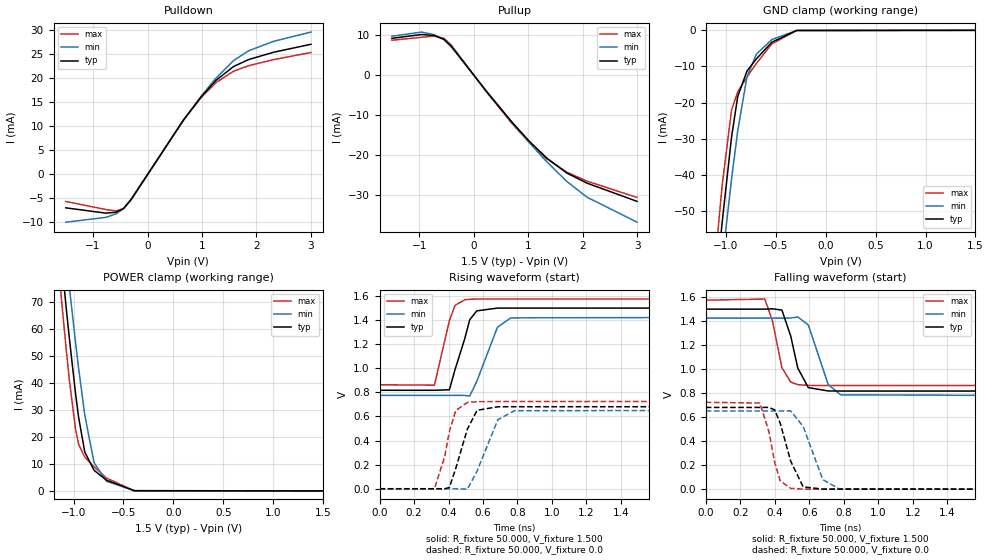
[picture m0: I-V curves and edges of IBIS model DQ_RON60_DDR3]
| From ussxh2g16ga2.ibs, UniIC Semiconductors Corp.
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|   Model DQ_RON60_DDR3
[Model] DQ_RON60_DDR3
Model_type I/O
Vinl =  0.615V
Vinh =  0.885V
Vmeas =  0.750V
Rref =  50.000
Vref =  0.750V
C_comp   0.966pF   0.965pF   0.967pF
[Model Spec]
Vinh   0.885V   0.847V   0.922V
Vinl   0.615V   0.577V   0.652V
Vmeas   0.750V   0.712V   0.787V
Vref   0.750V   0.712V   0.787V
Rref   50.000   NA   NA
[Temperature Range]   25.000   0.105k   -40.000
[Voltage Range]   1.500V   1.425V   1.575V
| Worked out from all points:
|   slope of the pulldown table from 0 to 0.225 V, typ, clamps not added: 56.5 ohm
|   slope of the pullup table from 0 to 0.225 V, typ, clamps not added: 57.4 ohm
|   GND clamp passes 1 mA (typ) near -0.43 V on its own axis
|   POWER clamp passes 1 mA (typ) near -0.52 V on its own axis
|   rising waveform, R_fixture 50.000, V_fixture 1.500: 20-80 % time 81.7ps typ, 104ps min, 66.8ps max; typ from 0.818 V to 1.5 V
|   rising waveform, R_fixture 50.000, V_fixture 0.0: 20-80 % time 84.4ps typ, 108ps min, 70.8ps max; typ from 0 V to 0.681 V
|   falling waveform, R_fixture 50.000, V_fixture 1.500: 20-80 % time 71.8ps typ, 88.2ps min, 63ps max; typ from 1.5 V to 0.818 V
|   falling waveform, R_fixture 50.000, V_fixture 0.0: 20-80 % time 76.4ps typ, 98.1ps min, 63.7ps max; typ from 0.681 V to 0 V
[Pulldown]
|Voltage   I(typ)   I(min)   I(max)
-1.5V     -7.077mA   -10.07mA   -5.748mA
-764mV    -8.187mA   -9.067mA   -7.434mA
-580mV    -7.998mA   -8.342mA   -7.72mA
-442mV    -7.252mA   -7.263mA   -7.217mA
-304mV    -5.41mA    -5.303mA   -5.451mA
662mV     11.26mA    11.19mA    11.24mA
984mV     16.05mA    16.16mA    15.87mA
1.26V     19.52mA    20mA       19.05mA
1.582V    22.39mA    23.63mA    21.41mA
1.858V    23.83mA    25.67mA    22.55mA
2.318V    25.36mA    27.63mA    23.82mA
3V        27.01mA    29.55mA    25.3mA
[Pullup]
|Voltage   I(typ)   I(min)   I(max)
-1.5V     9.205mA    9.732mA    8.722mA
-956mV    10.16mA    10.77mA    9.463mA
-726mV    9.917mA    10.15mA    9.772mA
-542mV    8.946mA    8.822mA    9.189mA
-404mV    7.122mA    6.977mA    7.402mA
240mV     -4.178mA   -4.138mA   -4.333mA
700mV     -11.77mA   -11.83mA   -12.12mA
1.022V    -16.63mA   -16.97mA   -16.98mA
1.344V    -20.88mA   -21.8mA    -21.06mA
1.712V    -24.62mA   -26.74mA   -24.4mA
2.08V     -27.14mA   -30.67mA   -26.64mA
3V        -31.73mA   -36.95mA   -30.74mA
[GND_clamp]
|Voltage   I(typ)   I(min)   I(max)
-1.5V     -194.2mA   -190.4mA   -200.2mA
-1.128V   -79.38mA   -87.94mA   -71.42mA
-1.097V   -70.36mA   -79.78mA   -61.46mA
-1.066V   -61.52mA   -71.73mA   -51.83mA
-1.035V   -52.91mA   -63.81mA   -42.69mA
-942mV    -29.54mA   -41.22mA   -22.03mA
-880mV    -18.29mA   -27.76mA   -17.02mA
-787mV    -11.24mA   -12.81mA   -12.91mA
-694mV    -7.909mA   -6.61mA    -9.178mA
-539mV    -3.3mA     -2.554mA   -3.76mA
-291mV    -42.28uA   -49.13uA   -38.22uA
1.5V      0A         0A         0A
[POWER_clamp]
|Voltage   I(typ)   I(min)   I(max)
-1.5V     238.9mA    246.7mA    236.4mA
-1.135V   91.01mA    108.5mA    76.96mA
-1.104V   79.29mA    97.43mA    64.51mA
-1.073V   67.84mA    86.49mA    52.53mA
-1.042V   56.75mA    75.77mA    41.28mA
-980mV    36.24mA    55.21mA    22.93mA
-949mV    27.34mA    45.53mA    17.31mA
-887mV    14.41mA    28.1mA     12.52mA
-794mV    7.645mA    10.44mA    8.93mA
-670mV    3.99mA     3.593mA    4.77mA
-391mV    72.25uA    122.5uA    45.94uA
1.5V      0A         0A         0A
[Ramp]
| variable   typ   min   max
dV/dt_r   0.409/84.474p   0.391/0.108n   0.434/70.864p
dV/dt_f   0.409/71.683p   0.390/87.910p   0.427/62.993p
R_load = 50.000
[Rising Waveform]
R_fixture= 50.000
V_fixture= 1.500
V_fixture_min= 1.425
V_fixture_max= 1.575
|time   V(typ)   V(min)   V(max)
0s        817.6mV    775.4mV    863.6mV
318ps     817.5mV    775.4mV    859.9mV
405ps     821.8mV    775.4mV    1.396V
438ps     990.5mV    775.4mV    1.523V
494ps     1.245V     775mV      1.569V
523ps     1.403V     769.9mV    1.573V
564ps     1.477V     891.3mV    1.575V
684ps     1.5V       1.341V     1.575V
762ps     1.5V       1.419V     1.575V
3ns       1.5V       1.425V     1.575V
[Rising Waveform]
R_fixture= 50.000
V_fixture= 0.0
V_fixture_min= 0.0
V_fixture_max= 0.0
|time   V(typ)   V(min)   V(max)
0s        223nV      2.174uV    104.7nV
318ps     -36.75uV   4.347uV    -722.7uV
378ps     -789.6uV   4.407uV    268.1mV
405ps     11.05mV    -8.692uV   476mV
442ps     168.5mV    770.5nV    649.6mV
509ps     494.3mV    -3.544mV   716.4mV
566ps     651.4mV    147.3mV    722.8mV
686ps     680.5mV    572.8mV    723.8mV
783ps     681mV      648.1mV    723.8mV
3ns       681.1mV    651.4mV    723.8mV
[Falling Waveform]
R_fixture= 50.000
V_fixture= 1.500
V_fixture_min= 1.425
V_fixture_max= 1.575
|time   V(typ)   V(min)   V(max)
0s        1.5V       1.425V     1.575V
342ps     1.5V       1.425V     1.584V
386ps     1.503V     1.425V     1.403V
441ps     1.492V     1.425V     1.013V
492ps     1.276V     1.426V     892.5mV
533ps     1.009V     1.435V     871mV
594ps     846.3mV    1.368V     864.6mV
709ps     818.3mV    872.4mV    863.6mV
781ps     817.6mV    786mV      863.6mV
3ns       817.6mV    775.4mV    863.6mV
[Falling Waveform]
R_fixture= 50.000
V_fixture= 0.0
V_fixture_min= 0.0
V_fixture_max= 0.0
|time   V(typ)   V(min)   V(max)
0s        681.1mV    651.4mV    723.8mV
313ps     681mV      651.4mV    717.6mV
366ps     681.5mV    651.4mV    479.3mV
399ps     660.4mV    651.4mV    223.9mV
431ps     550.8mV    651.3mV    69.25mV
492ps     232.8mV    652.2mV    6.928mV
564ps     19.6mV     522.7mV    460.1uV
678ps     316.2uV    79.14mV    5.411uV
771ps     10.14uV    3.522mV    366.2nV
3ns       258.2nV    2.202uV    185.5nV
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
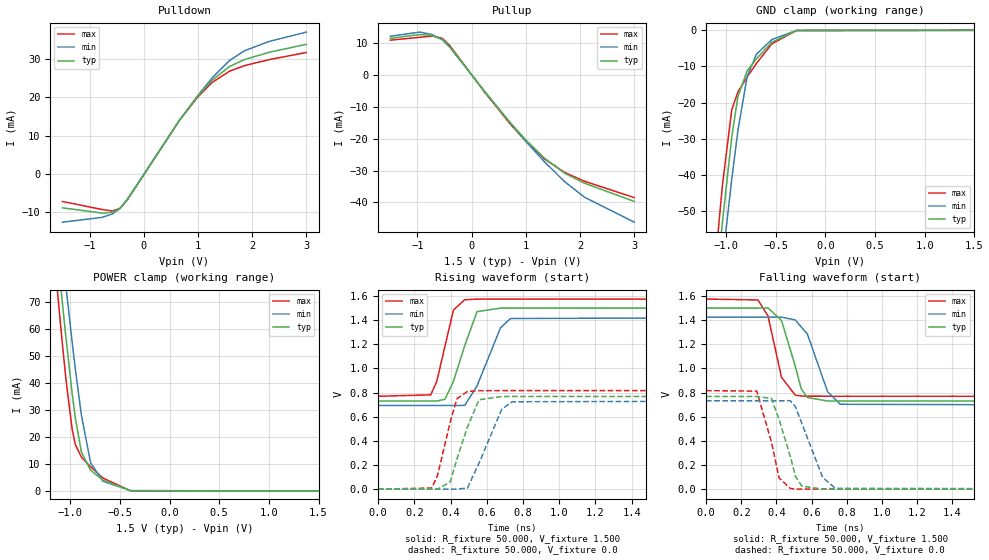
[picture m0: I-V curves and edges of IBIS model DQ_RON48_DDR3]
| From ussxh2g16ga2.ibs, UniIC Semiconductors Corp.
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|   Model DQ_RON48_DDR3
[Model] DQ_RON48_DDR3
Model_type I/O
Vinl =  0.615V
Vinh =  0.885V
Vmeas =  0.750V
Rref =  50.000
Vref =  0.750V
C_comp   0.966pF   0.965pF   0.967pF
[Model Spec]
Vinh   0.885V   0.847V   0.922V
Vinl   0.615V   0.577V   0.652V
Vmeas   0.750V   0.712V   0.787V
Vref   0.750V   0.712V   0.787V
Rref   50.000   NA   NA
[Temperature Range]   25.000   0.105k   -40.000
[Voltage Range]   1.500V   1.425V   1.575V
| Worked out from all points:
|   slope of the pulldown table from 0 to 0.225 V, typ, clamps not added: 45.2 ohm
|   slope of the pullup table from 0 to 0.225 V, typ, clamps not added: 45.9 ohm
|   GND clamp passes 1 mA (typ) near -0.43 V on its own axis
|   POWER clamp passes 1 mA (typ) near -0.52 V on its own axis
|   rising waveform, R_fixture 50.000, V_fixture 1.500: 20-80 % time 90.1ps typ, 119ps min, 72.2ps max; typ from 0.73 V to 1.5 V
|   rising waveform, R_fixture 50.000, V_fixture 0.0: 20-80 % time 91.2ps typ, 117ps min, 75.6ps max; typ from 0 V to 0.768 V
|   falling waveform, R_fixture 50.000, V_fixture 1.500: 20-80 % time 84.2ps typ, 105ps min, 72.3ps max; typ from 1.5 V to 0.73 V
|   falling waveform, R_fixture 50.000, V_fixture 0.0: 20-80 % time 90.2ps typ, 116ps min, 74.6ps max; typ from 0.768 V to 0 V
[Pulldown]
|Voltage   I(typ)   I(min)   I(max)
-1.5V     -8.855mA   -12.6mA    -7.198mA
-764mV    -10.24mA   -11.34mA   -9.305mA
-580mV    -10mA      -10.43mA   -9.66mA
-442mV    -9.069mA   -9.082mA   -9.029mA
-304mV    -6.766mA   -6.631mA   -6.819mA
662mV     14.08mA    14mA       14.06mA
984mV     20.07mA    20.21mA    19.85mA
1.26V     24.41mA    25.01mA    23.83mA
1.582V    28.01mA    29.57mA    26.79mA
1.858V    29.82mA    32.11mA    28.23mA
2.318V    31.73mA    34.58mA    29.82mA
3V        33.8mA     36.99mA    31.67mA
[Pullup]
|Voltage   I(typ)   I(min)   I(max)
-1.5V     11.52mA    12.17mA    10.93mA
-956mV    12.71mA    13.47mA    11.85mA
-726mV    12.41mA    12.69mA    12.23mA
-542mV    11.19mA    11.03mA    11.5mA
-404mV    8.909mA    8.725mA    9.263mA
240mV     -5.227mA   -5.175mA   -5.422mA
700mV     -14.73mA   -14.8mA    -15.17mA
1.022V    -20.8mA    -21.22mA   -21.25mA
1.344V    -26.12mA   -27.26mA   -26.36mA
1.712V    -30.8mA    -33.44mA   -30.54mA
2.08V     -33.96mA   -38.35mA   -33.35mA
3V        -39.7mA    -46.21mA   -38.49mA
[GND_clamp]
|Voltage   I(typ)   I(min)   I(max)
-1.5V     -194.2mA   -190.4mA   -200.2mA
-1.128V   -79.38mA   -87.94mA   -71.42mA
-1.097V   -70.36mA   -79.78mA   -61.46mA
-1.066V   -61.52mA   -71.73mA   -51.83mA
-1.035V   -52.91mA   -63.81mA   -42.69mA
-942mV    -29.54mA   -41.22mA   -22.03mA
-880mV    -18.29mA   -27.76mA   -17.02mA
-787mV    -11.24mA   -12.81mA   -12.91mA
-694mV    -7.909mA   -6.61mA    -9.178mA
-539mV    -3.3mA     -2.554mA   -3.76mA
-291mV    -42.28uA   -49.13uA   -38.22uA
1.5V      0A         0A         0A
[POWER_clamp]
|Voltage   I(typ)   I(min)   I(max)
-1.5V     238.9mA    246.7mA    236.4mA
-1.135V   91.01mA    108.5mA    76.96mA
-1.104V   79.29mA    97.43mA    64.51mA
-1.073V   67.84mA    86.49mA    52.53mA
-1.042V   56.75mA    75.77mA    41.28mA
-980mV    36.24mA    55.21mA    22.93mA
-949mV    27.34mA    45.53mA    17.31mA
-887mV    14.41mA    28.1mA     12.52mA
-794mV    7.645mA    10.44mA    8.93mA
-670mV    3.99mA     3.593mA    4.77mA
-391mV    72.25uA    122.5uA    45.94uA
1.5V      0A         0A         0A
[Ramp]
| variable   typ   min   max
dV/dt_r   0.461/90.981p   0.439/0.117n   0.490/75.637p
dV/dt_f   0.462/83.868p   0.439/0.105n   0.483/72.416p
R_load = 50.000
[Rising Waveform]
R_fixture= 50.000
V_fixture= 1.500
V_fixture_min= 1.425
V_fixture_max= 1.575
|time   V(typ)   V(min)   V(max)
0s        729.8mV    693.5mV    769.8mV
290ps     729.8mV    693.5mV    781.2mV
324ps     729.8mV    693.5mV    894.4mV
369ps     745.1mV    693.5mV    1.186V
416ps     894.5mV    693.6mV    1.485V
478ps     1.189V     694mV      1.569V
546ps     1.471V     855.1mV    1.575V
676ps     1.5V       1.338V     1.575V
731ps     1.5V       1.414V     1.575V
3ns       1.5V       1.425V     1.575V
[Rising Waveform]
R_fixture= 50.000
V_fixture= 0.0
V_fixture_min= 0.0
V_fixture_max= 0.0
|time   V(typ)   V(min)   V(max)
0s        208.5nV    1.952uV    107.7nV
296ps     -18.19uV   4.75uV     9.245mV
328ps     122.6uV    6.61uV     115.8mV
398ps     60.93mV    4.586uV    556.4mV
435ps     249.9mV    197.2uV    749.6mV
493ps     515.5mV    9.333mV    809.4mV
557ps     740.9mV    215.5mV    815.9mV
683ps     767.7mV    664.1mV    816.5mV
741ps     767.9mV    724.1mV    816.5mV
3ns       767.9mV    732.3mV    816.5mV
[Falling Waveform]
R_fixture= 50.000
V_fixture= 1.500
V_fixture_min= 1.425
V_fixture_max= 1.575
|time   V(typ)   V(min)   V(max)
0s        1.5V       1.425V     1.575V
295ps     1.5V       1.425V     1.568V
352ps     1.502V     1.425V     1.435V
429ps     1.397V     1.425V     926.7mV
507ps     1.02V      1.402V     778.6mV
541ps     831.9mV    1.344V     772.3mV
576ps     759.5mV    1.286V     770.4mV
691ps     730.3mV    807.4mV    769.8mV
763ps     729.9mV    703.4mV    769.8mV
3ns       729.8mV    693.5mV    769.8mV
[Falling Waveform]
R_fixture= 50.000
V_fixture= 0.0
V_fixture_min= 0.0
V_fixture_max= 0.0
|time   V(typ)   V(min)   V(max)
0s        767.9mV    732.3mV    816.5mV
288ps     767.9mV    732.3mV    812.1mV
372ps     751.8mV    732.3mV    388.2mV
415ps     577.3mV    732.2mV    93.48mV
479ps     271.5mV    732.9mV    6.137mV
508ps     106.7mV    683.2mV    1.781mV
545ps     24.69mV    542.6mV    357.2uV
663ps     202.6uV    97.43mV    2.2uV
735ps     10.31uV    6.917mV    389.8nV
3ns       217.6nV    1.935uV    247.7nV
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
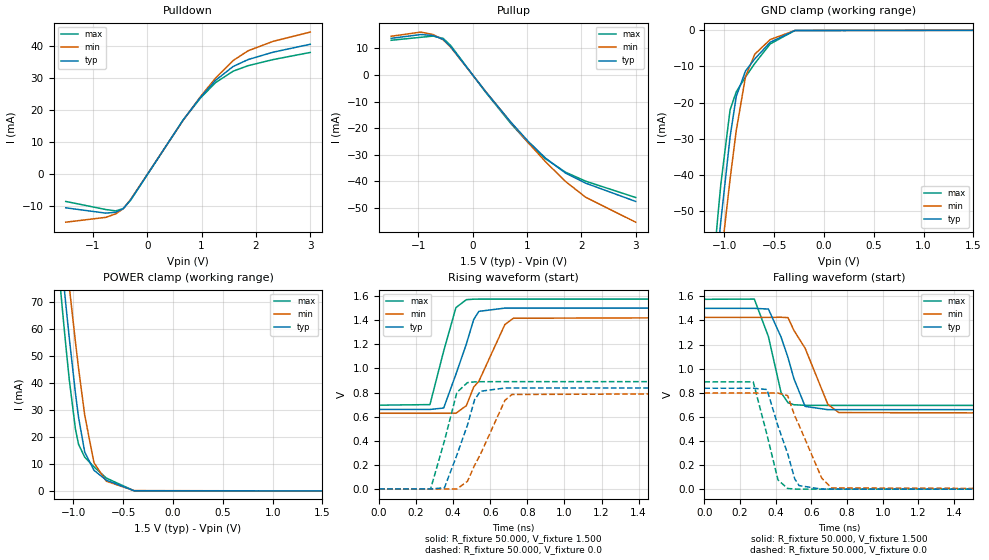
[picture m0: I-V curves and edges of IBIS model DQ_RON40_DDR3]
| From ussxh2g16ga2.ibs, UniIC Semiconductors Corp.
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|   Model DQ_RON40_DDR3
[Model] DQ_RON40_DDR3
Model_type I/O
Vinl =  0.615V
Vinh =  0.885V
Vmeas =  0.750V
Rref =  50.000
Vref =  0.750V
C_comp   0.966pF   0.965pF   0.967pF
[Model Spec]
Vinh   0.885V   0.847V   0.922V
Vinl   0.615V   0.577V   0.652V
Vmeas   0.750V   0.712V   0.787V
Vref   0.750V   0.712V   0.787V
Rref   50.000   NA   NA
[Temperature Range]   25.000   0.105k   -40.000
[Voltage Range]   1.500V   1.425V   1.575V
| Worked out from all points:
|   slope of the pulldown table from 0 to 0.225 V, typ, clamps not added: 37.7 ohm
|   slope of the pullup table from 0 to 0.225 V, typ, clamps not added: 38.3 ohm
|   GND clamp passes 1 mA (typ) near -0.43 V on its own axis
|   POWER clamp passes 1 mA (typ) near -0.52 V on its own axis
|   rising waveform, R_fixture 50.000, V_fixture 1.500: 20-80 % time 119ps typ, 164ps min, 91.2ps max; typ from 0.659 V to 1.5 V
|   rising waveform, R_fixture 50.000, V_fixture 0.0: 20-80 % time 108ps typ, 151ps min, 83.3ps max; typ from 0 V to 0.837 V
|   falling waveform, R_fixture 50.000, V_fixture 1.500: 20-80 % time 112ps typ, 153ps min, 86.8ps max; typ from 1.5 V to 0.659 V
|   falling waveform, R_fixture 50.000, V_fixture 0.0: 20-80 % time 107ps typ, 143ps min, 85.9ps max; typ from 0.837 V to 0 V
[Pulldown]
|Voltage   I(typ)   I(min)   I(max)
-1.5V     -10.61mA   -15.1mA    -8.617mA
-764mV    -12.27mA   -13.59mA   -11.14mA
-580mV    -11.99mA   -12.5mA    -11.57mA
-442mV    -10.87mA   -10.89mA   -10.82mA
-304mV    -8.107mA   -7.946mA   -8.167mA
662mV     16.87mA    16.77mA    16.84mA
984mV     24.04mA    24.22mA    23.77mA
1.26V     29.25mA    29.97mA    28.54mA
1.582V    33.55mA    35.41mA    32.08mA
1.858V    35.71mA    38.46mA    33.8mA
2.318V    38.01mA    41.4mA     35.7mA
3V        40.48mA    44.28mA    37.92mA
[Pullup]
|Voltage   I(typ)   I(min)   I(max)
-1.5V     13.8mA     14.58mA    13.07mA
-956mV    15.23mA    16.15mA    14.19mA
-726mV    14.86mA    15.21mA    14.65mA
-542mV    13.41mA    13.22mA    13.77mA
-404mV    10.67mA    10.45mA    11.09mA
240mV     -6.259mA   -6.199mA   -6.49mA
700mV     -17.64mA   -17.73mA   -18.15mA
1.022V    -24.91mA   -25.42mA   -25.43mA
1.344V    -31.28mA   -32.66mA   -31.54mA
1.712V    -36.88mA   -40.06mA   -36.54mA
2.08V     -40.64mA   -45.93mA   -39.9mA
3V        -47.51mA   -55.31mA   -46.03mA
[GND_clamp]
|Voltage   I(typ)   I(min)   I(max)
-1.5V     -194.2mA   -190.4mA   -200.2mA
-1.128V   -79.38mA   -87.94mA   -71.42mA
-1.097V   -70.36mA   -79.78mA   -61.46mA
-1.066V   -61.52mA   -71.73mA   -51.83mA
-1.035V   -52.91mA   -63.81mA   -42.69mA
-942mV    -29.54mA   -41.22mA   -22.03mA
-880mV    -18.29mA   -27.76mA   -17.02mA
-787mV    -11.24mA   -12.81mA   -12.91mA
-694mV    -7.909mA   -6.61mA    -9.178mA
-539mV    -3.3mA     -2.554mA   -3.76mA
-291mV    -42.28uA   -49.13uA   -38.22uA
1.5V      0A         0A         0A
[POWER_clamp]
|Voltage   I(typ)   I(min)   I(max)
-1.5V     238.9mA    246.7mA    236.4mA
-1.135V   91.01mA    108.5mA    76.96mA
-1.104V   79.29mA    97.43mA    64.51mA
-1.073V   67.84mA    86.49mA    52.53mA
-1.042V   56.75mA    75.77mA    41.28mA
-980mV    36.24mA    55.21mA    22.93mA
-949mV    27.34mA    45.53mA    17.31mA
-887mV    14.41mA    28.1mA     12.52mA
-794mV    7.645mA    10.44mA    8.93mA
-670mV    3.99mA     3.593mA    4.77mA
-391mV    72.25uA    122.5uA    45.94uA
1.5V      0A         0A         0A
[Ramp]
| variable   typ   min   max
dV/dt_r   0.502/0.108n   0.478/0.151n   0.534/83.194p
dV/dt_f   0.504/0.112n   0.478/0.153n   0.528/86.940p
R_load = 50.000
[Rising Waveform]
R_fixture= 50.000
V_fixture= 1.500
V_fixture_min= 1.425
V_fixture_max= 1.575
|time   V(typ)   V(min)   V(max)
0s        659.5mV    627.7mV    694.9mV
275ps     659.4mV    627.7mV    699.6mV
349ps     671.3mV    627.7mV    1.144V
415ps     951.4mV    627.8mV    1.504V
471ps     1.201V     690.6mV    1.57V
511ps     1.406V     845.4mV    1.574V
539ps     1.473V     894.2mV    1.575V
679ps     1.5V       1.364V     1.575V
725ps     1.5V       1.416V     1.575V
3ns       1.5V       1.425V     1.575V
[Rising Waveform]
R_fixture= 50.000
V_fixture= 0.0
V_fixture_min= 0.0
V_fixture_max= 0.0
|time   V(typ)   V(min)   V(max)
0s        197.4nV    1.776uV    110.9nV
278ps     -66.61uV   4.027uV    -1.742mV
353ps     9.699mV    -42.77uV   398.3mV
420ps     280.4mV    -46.21uV   800.1mV
477ps     529.5mV    63.01mV    882mV
516ps     741.7mV    197.1mV    888.3mV
547ps     810.2mV    287.2mV    889.5mV
679ps     837.3mV    734.5mV    889.9mV
717ps     837.4mV    783.5mV    889.9mV
3ns       837.4mV    797.4mV    889.9mV
[Falling Waveform]
R_fixture= 50.000
V_fixture= 1.500
V_fixture_min= 1.425
V_fixture_max= 1.575
|time   V(typ)   V(min)   V(max)
0s        1.5V       1.425V     1.575V
280ps     1.5V       1.425V     1.577V
359ps     1.494V     1.425V     1.266V
430ps     1.262V     1.426V     801.3mV
469ps     1.091V     1.423V     717mV
502ps     916.9mV    1.317V     700.5mV
565ps     686.6mV    1.169V     695.4mV
692ps     659.6mV    704.7mV    694.9mV
754ps     659.5mV    635.3mV    694.9mV
3ns       659.5mV    627.7mV    694.9mV
[Falling Waveform]
R_fixture= 50.000
V_fixture= 0.0
V_fixture_min= 0.0
V_fixture_max= 0.0
|time   V(typ)   V(min)   V(max)
0s        837.4mV    797.4mV    889.9mV
274ps     837.4mV    797.4mV    890mV
351ps     826.5mV    797.4mV    451.5mV
413ps     523.3mV    797.2mV    75.97mV
467ps     295mV      775.8mV    5.888mV
507ps     84.19mV    606.7mV    862.8uV
531ps     29.82mV    530.4mV    295.8uV
658ps     103.2uV    91.18mV    882.3nV
713ps     9.042uV    10.18mV    290.8nV
3ns       226.3nV    1.742uV    156.2nV
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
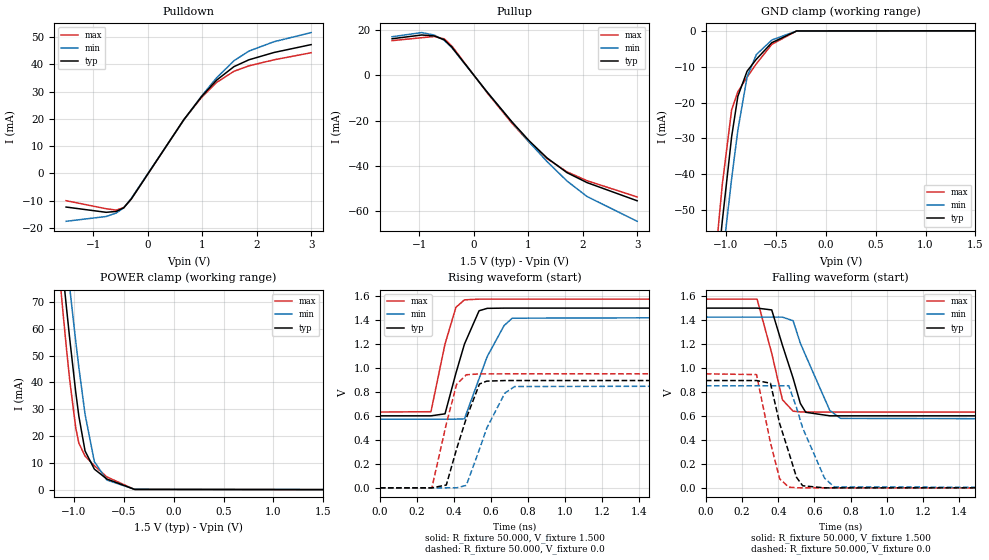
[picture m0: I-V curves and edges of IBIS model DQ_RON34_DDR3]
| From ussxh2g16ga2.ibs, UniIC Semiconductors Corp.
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|   Model DQ_RON34_DDR3
[Model] DQ_RON34_DDR3
Model_type I/O
Vinl =  0.615V
Vinh =  0.885V
Vmeas =  0.750V
Rref =  50.000
Vref =  0.750V
C_comp   0.966pF   0.965pF   0.967pF
[Model Spec]
Vinh   0.885V   0.847V   0.922V
Vinl   0.615V   0.577V   0.652V
Vmeas   0.750V   0.712V   0.787V
Vref   0.750V   0.712V   0.787V
Rref   50.000   NA   NA
[Temperature Range]   25.000   0.105k   -40.000
[Voltage Range]   1.500V   1.425V   1.575V
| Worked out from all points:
|   slope of the pulldown table from 0 to 0.225 V, typ, clamps not added: 32.3 ohm
|   slope of the pullup table from 0 to 0.225 V, typ, clamps not added: 32.8 ohm
|   GND clamp passes 1 mA (typ) near -0.43 V on its own axis
|   POWER clamp passes 1 mA (typ) near -0.52 V on its own axis
|   rising waveform, R_fixture 50.000, V_fixture 1.500: 20-80 % time 114ps typ, 154ps min, 89.1ps max; typ from 0.601 V to 1.5 V
|   rising waveform, R_fixture 50.000, V_fixture 0.0: 20-80 % time 108ps typ, 144ps min, 85.2ps max; typ from 0 V to 0.896 V
|   falling waveform, R_fixture 50.000, V_fixture 1.500: 20-80 % time 111ps typ, 147ps min, 90.2ps max; typ from 1.5 V to 0.601 V
|   falling waveform, R_fixture 50.000, V_fixture 0.0: 20-80 % time 102ps typ, 135ps min, 83.7ps max; typ from 0.896 V to 0 V
[Pulldown]
|Voltage   I(typ)   I(min)   I(max)
-1.5V     -12.39mA   -17.62mA   -10.06mA
-764mV    -14.32mA   -15.86mA   -13.01mA
-580mV    -13.99mA   -14.59mA   -13.51mA
-442mV    -12.68mA   -12.69mA   -12.62mA
-304mV    -9.452mA   -9.265mA   -9.524mA
662mV     19.67mA    19.56mA    19.64mA
984mV     28.04mA    28.24mA    27.73mA
1.26V     34.11mA    34.94mA    33.29mA
1.582V    39.13mA    41.29mA    37.42mA
1.858V    41.65mA    44.85mA    39.43mA
2.318V    44.33mA    48.28mA    41.64mA
3V        47.22mA    51.64mA    44.24mA
[Pullup]
|Voltage   I(typ)   I(min)   I(max)
-1.5V     16.11mA    17mA       15.27mA
-956mV    17.77mA    18.84mA    16.57mA
-726mV    17.35mA    17.74mA    17.1mA
-542mV    15.64mA    15.42mA    16.07mA
-404mV    12.45mA    12.19mA    12.94mA
240mV     -7.301mA   -7.23mA    -7.573mA
700mV     -20.57mA   -20.67mA   -21.19mA
1.022V    -29.06mA   -29.64mA   -29.68mA
1.344V    -36.49mA   -38.08mA   -36.81mA
1.712V    -43.02mA   -46.71mA   -42.65mA
2.08V     -47.41mA   -53.55mA   -46.57mA
3V        -55.43mA   -64.49mA   -53.74mA
[GND_clamp]
|Voltage   I(typ)   I(min)   I(max)
-1.5V     -194.2mA   -190.4mA   -200.2mA
-1.128V   -79.38mA   -87.94mA   -71.42mA
-1.097V   -70.36mA   -79.78mA   -61.46mA
-1.066V   -61.52mA   -71.73mA   -51.83mA
-1.035V   -52.91mA   -63.81mA   -42.69mA
-942mV    -29.54mA   -41.22mA   -22.03mA
-880mV    -18.29mA   -27.76mA   -17.02mA
-787mV    -11.24mA   -12.81mA   -12.91mA
-694mV    -7.909mA   -6.61mA    -9.178mA
-539mV    -3.3mA     -2.554mA   -3.76mA
-291mV    -42.28uA   -49.13uA   -38.22uA
1.5V      0A         0A         0A
[POWER_clamp]
|Voltage   I(typ)   I(min)   I(max)
-1.5V     238.9mA    246.7mA    236.4mA
-1.135V   91.01mA    108.5mA    76.96mA
-1.104V   79.29mA    97.43mA    64.51mA
-1.073V   67.84mA    86.49mA    52.53mA
-1.042V   56.75mA    75.77mA    41.28mA
-980mV    36.24mA    55.21mA    22.93mA
-949mV    27.34mA    45.53mA    17.31mA
-887mV    14.41mA    28.1mA     12.52mA
-794mV    7.645mA    10.44mA    8.93mA
-670mV    3.99mA     3.593mA    4.77mA
-391mV    72.25uA    122.5uA    45.94uA
1.5V      0A         0A         0A
[Ramp]
| variable   typ   min   max
dV/dt_r   0.537/0.108n   0.511/0.144n   0.571/85.190p
dV/dt_f   0.539/0.111n   0.511/0.148n   0.565/90.271p
R_load = 50.000
[Rising Waveform]
R_fixture= 50.000
V_fixture= 1.500
V_fixture_min= 1.425
V_fixture_max= 1.575
|time   V(typ)   V(min)   V(max)
0s        601.1mV    573mV      632.7mV
276ps     601mV      573mV      635.5mV
352ps     617.7mV    573mV      1.201V
411ps     957.8mV    573.4mV    1.507V
457ps     1.2V       575.7mV    1.569V
536ps     1.478V     911.3mV    1.575V
580ps     1.498V     1.096V     1.575V
671ps     1.5V       1.354V     1.575V
715ps     1.5V       1.416V     1.575V
3ns       1.5V       1.425V     1.575V
[Rising Waveform]
R_fixture= 50.000
V_fixture= 0.0
V_fixture_min= 0.0
V_fixture_max= 0.0
|time   V(typ)   V(min)   V(max)
0s        187.9nV    1.628uV    113.1nV
281ps     -80.66uV   4.392uV    278uV
359ps     23.7mV     -61.9uV    534.3mV
415ps     326.8mV    506.5uV    864.9mV
467ps     581.1mV    20.58mV    943.8mV
538ps     866.5mV    321.3mV    951.1mV
577ps     890.5mV    497.2mV    951.3mV
675ps     895.5mV    790.3mV    951.4mV
728ps     895.6mV    845.7mV    951.4mV
3ns       895.6mV    851.7mV    951.4mV
[Falling Waveform]
R_fixture= 50.000
V_fixture= 1.500
V_fixture_min= 1.425
V_fixture_max= 1.575
|time   V(typ)   V(min)   V(max)
0s        1.5V       1.425V     1.575V
283ps     1.5V       1.425V     1.575V
364ps     1.485V     1.425V     1.123V
423ps     1.191V     1.425V     735.6mV
482ps     916.2mV    1.395V     639.9mV
522ps     704.9mV    1.208V     633.9mV
552ps     630.6mV    1.103V     633mV
685ps     601.2mV    645.9mV    632.7mV
745ps     601.1mV    579.6mV    632.7mV
3ns       601.1mV    573mV      632.7mV
[Falling Waveform]
R_fixture= 50.000
V_fixture= 0.0
V_fixture_min= 0.0
V_fixture_max= 0.0
|time   V(typ)   V(min)   V(max)
0s        895.6mV    851.7mV    951.4mV
280ps     895.5mV    851.7mV    945.4mV
357ps     873.1mV    851.7mV    375.7mV
408ps     535.8mV    851.3mV    75.5mV
458ps     298.1mV    852.5mV    5.725mV
501ps     87.93mV    669.7mV    607.7uV
535ps     17.57mV    499.2mV    103uV
656ps     52.39uV    80.98mV    506.7nV
709ps     4.46uV     8.242mV    247.8nV
3ns       165.2nV    1.573uV    89.97nV
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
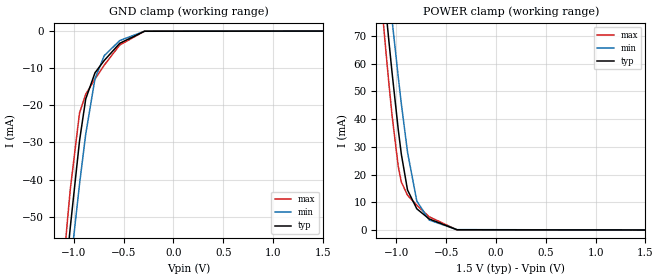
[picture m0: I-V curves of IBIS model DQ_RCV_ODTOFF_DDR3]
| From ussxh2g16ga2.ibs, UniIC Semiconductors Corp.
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|   Model DQ_RCV_ODTOFF_DDR3
[Model] DQ_RCV_ODTOFF_DDR3
Model_type Input
Vinl =  0.615V
Vinh =  0.885V
C_comp   0.966pF   0.965pF   0.967pF
[Model Spec]
Vinh   0.885V   0.847V   0.922V
Vinl   0.615V   0.577V   0.652V
[Temperature Range]   25.000   0.105k   -40.000
[Voltage Range]   1.500V   1.425V   1.575V
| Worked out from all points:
|   GND clamp passes 1 mA (typ) near -0.43 V on its own axis
|   POWER clamp passes 1 mA (typ) near -0.52 V on its own axis
[GND_clamp]
|Voltage   I(typ)   I(min)   I(max)
-1.5V     -194.2mA   -190.4mA   -200.2mA
-1.128V   -79.38mA   -87.94mA   -71.42mA
-1.097V   -70.36mA   -79.78mA   -61.46mA
-1.066V   -61.52mA   -71.73mA   -51.83mA
-1.035V   -52.91mA   -63.81mA   -42.69mA
-942mV    -29.54mA   -41.22mA   -22.03mA
-880mV    -18.29mA   -27.76mA   -17.02mA
-787mV    -11.24mA   -12.81mA   -12.91mA
-694mV    -7.909mA   -6.61mA    -9.178mA
-539mV    -3.3mA     -2.554mA   -3.76mA
-291mV    -42.28uA   -49.13uA   -38.22uA
1.5V      0A         0A         0A
[POWER_clamp]
|Voltage   I(typ)   I(min)   I(max)
-1.5V     238.9mA    246.7mA    236.4mA
-1.135V   91.01mA    108.5mA    76.96mA
-1.104V   79.29mA    97.43mA    64.51mA
-1.073V   67.84mA    86.49mA    52.53mA
-1.042V   56.75mA    75.77mA    41.28mA
-980mV    36.24mA    55.21mA    22.93mA
-949mV    27.34mA    45.53mA    17.31mA
-887mV    14.41mA    28.1mA     12.52mA
-794mV    7.645mA    10.44mA    8.93mA
-670mV    3.99mA     3.593mA    4.77mA
-391mV    72.25uA    122.5uA    45.94uA
1.5V      0A         0A         0A
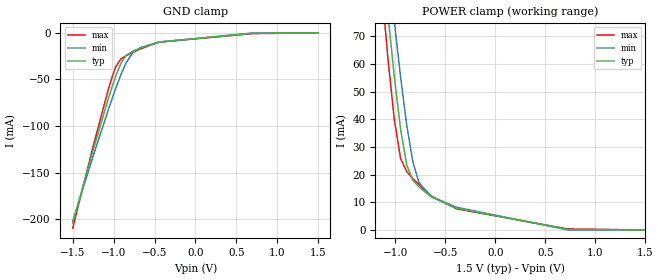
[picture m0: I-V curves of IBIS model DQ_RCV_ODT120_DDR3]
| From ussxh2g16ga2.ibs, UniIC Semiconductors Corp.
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|   Model DQ_RCV_ODT120_DDR3
[Model] DQ_RCV_ODT120_DDR3
Model_type Input
Vinl =  0.615V
Vinh =  0.885V
C_comp   0.966pF   0.965pF   0.967pF
[Model Spec]
Vinh   0.885V   0.847V   0.922V
Vinl   0.615V   0.577V   0.652V
[Temperature Range]   25.000   0.105k   -40.000
[Voltage Range]   1.500V   1.425V   1.575V
[GND_clamp]
|Voltage   I(typ)   I(min)   I(max)
-1.5V     -204mA     -202.1mA   -209.5mA
-1.252V   -126.2mA   -132.7mA   -122.2mA
-1.066V   -70.97mA   -82.65mA   -60.88mA
-1.004V   -54.01mA   -66.86mA   -43.36mA
-973mV    -46.13mA   -59.24mA   -36.24mA
-911mV    -32.58mA   -44.86mA   -27.9mA
-849mV    -24.13mA   -32.33mA   -24.53mA
-756mV    -19.19mA   -20.11mA   -20.57mA
-663mV    -15.91mA   -15.51mA   -16.87mA
-446mV    -9.729mA   -9.991mA   -9.903mA
701mV     -368.9uA   -102.8uA   -759.9uA
1.5V      0A         0A         0A
[POWER_clamp]
|Voltage   I(typ)   I(min)   I(max)
-1.5V     248mA      256.5mA    245.1mA
-1.197V   124.2mA    141.1mA    111.3mA
-1.073V   76.94mA    96.3mA     61.05mA
-1.011V   55.22mA    75.09mA    39.7mA
-949mV    36.37mA    55.25mA    25.83mA
-887mV    23.4mA     37.74mA    21.04mA
-825mV    17.89mA    24.39mA    18.56mA
-763mV    15.47mA    16.96mA    16.32mA
-639mV    11.89mA    12.02mA    12.22mA
-391mV    7.841mA    8.223mA    7.628mA
725mV     206.1uA    0A         374uA
1.5V      0A         0A         0A
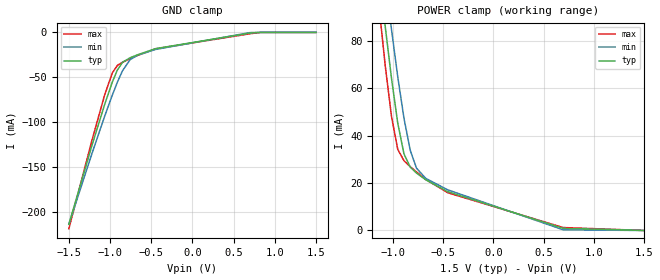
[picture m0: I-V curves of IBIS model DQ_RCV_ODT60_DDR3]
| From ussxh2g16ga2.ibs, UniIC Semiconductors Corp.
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|   Model DQ_RCV_ODT60_DDR3
[Model] DQ_RCV_ODT60_DDR3
Model_type Input
Vinl =  0.615V
Vinh =  0.885V
C_comp   0.966pF   0.965pF   0.967pF
[Model Spec]
Vinh   0.885V   0.847V   0.922V
Vinl   0.615V   0.577V   0.652V
[Temperature Range]   25.000   0.105k   -40.000
[Voltage Range]   1.500V   1.425V   1.575V
[GND_clamp]
|Voltage   I(typ)   I(min)   I(max)
-1.5V     -213.6mA   -213.7mA   -218.6mA
-1.221V   -126.2mA   -135.2mA   -120.5mA
-1.066V   -80.29mA   -93.47mA   -69.73mA
-973mV    -55.38mA   -69.87mA   -45.06mA
-911mV    -41.77mA   -55.35mA   -36.7mA
-849mV    -33.26mA   -42.68mA   -33.31mA
-756mV    -28.21mA   -30.22mA   -29.32mA
-663mV    -24.81mA   -25.34mA   -25.56mA
-446mV    -18.08mA   -18.94mA   -18.22mA
701mV     -718.2uA   -199.2uA   -1.484mA
825mV     0A         0A         0A
1.5V      0A         0A         0A
[POWER_clamp]
|Voltage   I(typ)   I(min)   I(max)
-1.5V     257mA      266.3mA    253.6mA
-1.197V   133.2mA    150.8mA    119.7mA
-1.073V   85.93mA    106mA      69.44mA
-1.011V   64.18mA    84.76mA    48.09mA
-949mV    45.29mA    64.86mA    34.22mA
-887mV    32.28mA    47.28mA    29.42mA
-825mV    26.72mA    33.84mA    26.94mA
-763mV    24.23mA    26.29mA    24.68mA
-670mV    21.35mA    21.95mA    21.48mA
-453mV    16.37mA    17.15mA    15.93mA
694mV     904.4uA    283.7uA    1.234mA
1.5V      0A         0A         0A
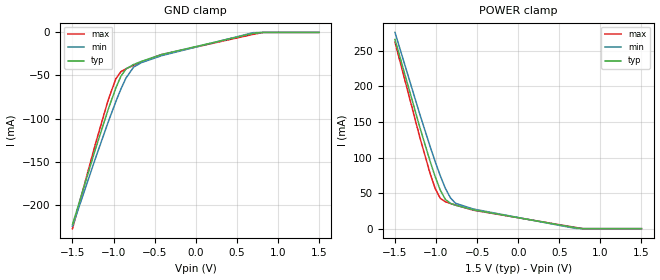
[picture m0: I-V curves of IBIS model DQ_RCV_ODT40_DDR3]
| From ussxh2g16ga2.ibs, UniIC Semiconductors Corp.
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|   Model DQ_RCV_ODT40_DDR3
[Model] DQ_RCV_ODT40_DDR3
Model_type Input
Vinl =  0.615V
Vinh =  0.885V
C_comp   0.966pF   0.965pF   0.967pF
[Model Spec]
Vinh   0.885V   0.847V   0.922V
Vinl   0.615V   0.577V   0.652V
[Temperature Range]   25.000   0.105k   -40.000
[Voltage Range]   1.500V   1.425V   1.575V
[GND_clamp]
|Voltage   I(typ)   I(min)   I(max)
-1.5V     -223.3mA   -225.3mA   -227.9mA
-1.221V   -135.7mA   -146.4mA   -129.6mA
-1.066V   -89.68mA   -104.3mA   -78.73mA
-973mV    -64.69mA   -80.52mA   -54.02mA
-911mV    -51.03mA   -65.87mA   -45.65mA
-849mV    -42.46mA   -53.05mA   -42.23mA
-756mV    -37.3mA    -40.35mA   -38.2mA
-663mV    -33.76mA   -35.19mA   -34.38mA
-415mV    -25.64mA   -27.02mA   -25.78mA
701mV     -1.089mA   -305.8uA   -2.245mA
825mV     0A         0A         0A
1.5V      0A         0A         0A
[POWER_clamp]
|Voltage   I(typ)   I(min)   I(max)
-1.5V     266.1mA    276mA      262.2mA
-1.197V   142.3mA    160.6mA    128.2mA
-1.073V   94.97mA    115.8mA    77.9mA
-1.011V   73.19mA    94.45mA    56.55mA
-949mV    54.27mA    74.5mA     42.69mA
-887mV    41.21mA    56.84mA    37.89mA
-825mV    35.59mA    43.31mA    35.39mA
-763mV    33.04mA    35.66mA    33.11mA
-546mV    26.48mA    27.63mA    25.97mA
694mV     1.343mA    417.7uA    1.831mA
787mV     0A         0A         0A
1.5V      0A         0A         0A
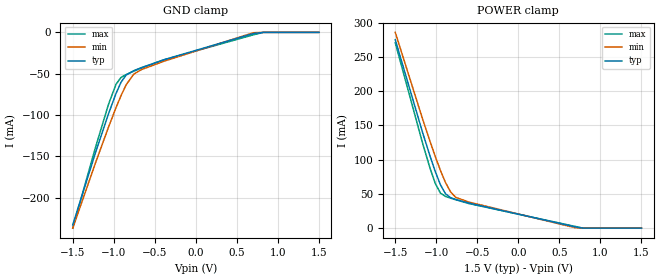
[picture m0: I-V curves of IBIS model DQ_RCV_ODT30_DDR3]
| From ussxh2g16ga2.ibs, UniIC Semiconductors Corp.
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|   Model DQ_RCV_ODT30_DDR3
[Model] DQ_RCV_ODT30_DDR3
Model_type Input
Vinl =  0.615V
Vinh =  0.885V
C_comp   0.966pF   0.965pF   0.967pF
[Model Spec]
Vinh   0.885V   0.847V   0.922V
Vinl   0.615V   0.577V   0.652V
[Temperature Range]   25.000   0.105k   -40.000
[Voltage Range]   1.500V   1.425V   1.575V
[GND_clamp]
|Voltage   I(typ)   I(min)   I(max)
-1.5V     -233mA     -237mA     -237mA
-1.221V   -145.1mA   -157.5mA   -138.6mA
-1.066V   -99.03mA   -115.2mA   -87.62mA
-973mV    -73.97mA   -91.18mA   -62.88mA
-911mV    -60.25mA   -76.39mA   -54.48mA
-849mV    -51.62mA   -63.43mA   -51.05mA
-756mV    -46.36mA   -50.48mA   -46.99mA
-663mV    -42.67mA   -45.05mA   -43.11mA
-384mV    -32.97mA   -34.78mA   -33.11mA
701mV     -1.444mA   -406.1uA   -2.979mA
825mV     0A         0A         0A
1.5V      0A         0A         0A
[POWER_clamp]
|Voltage   I(typ)   I(min)   I(max)
-1.5V     275.1mA    285.8mA    270.6mA
-1.166V   139.2mA    159mA      123.5mA
-1.073V   104mA      125.5mA    86.29mA
-1.011V   82.16mA    104.1mA    64.95mA
-949mV    63.21mA    84.11mA    51.08mA
-887mV    50.1mA     66.38mA    46.28mA
-825mV    44.43mA    52.76mA    43.78mA
-763mV    41.81mA    44.99mA    41.47mA
-608mV    36.68mA    38.21mA    36.03mA
694mV     1.795mA    557.8uA    2.446mA
787mV     0A         0A         0A
1.5V      0A         0A         0A
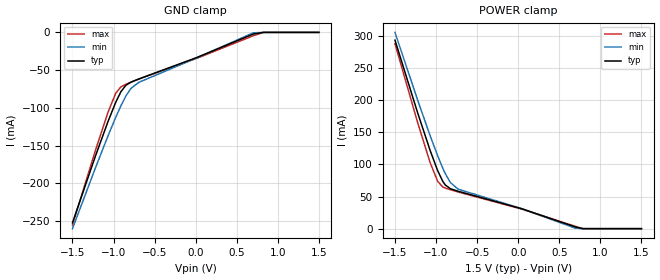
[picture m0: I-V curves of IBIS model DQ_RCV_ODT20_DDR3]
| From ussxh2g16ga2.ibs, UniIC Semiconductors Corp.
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|   Model DQ_RCV_ODT20_DDR3
[Model] DQ_RCV_ODT20_DDR3
Model_type Input
Vinl =  0.615V
Vinh =  0.885V
C_comp   0.966pF   0.965pF   0.967pF
[Model Spec]
Vinh   0.885V   0.847V   0.922V
Vinl   0.615V   0.577V   0.652V
[Temperature Range]   25.000   0.105k   -40.000
[Voltage Range]   1.500V   1.425V   1.575V
[GND_clamp]
|Voltage   I(typ)   I(min)   I(max)
-1.5V     -252.3mA   -260.1mA   -255.3mA
-1.221V   -164mA     -179.7mA   -156.5mA
-1.066V   -117.7mA   -136.8mA   -105.4mA
-973mV    -92.5mA    -112.4mA   -80.64mA
-911mV    -78.68mA   -97.36mA   -72.2mA
-849mV    -69.93mA   -84.11mA   -68.73mA
-787mV    -65.87mA   -74.09mA   -65.95mA
-694mV    -61.79mA   -66.3mA    -61.92mA
19mV      -33.06mA   -33.45mA   -34.13mA
701mV     -2.159mA   -605.8uA   -4.458mA
825mV     0A         0A         0A
1.5V      0A         0A         0A
[POWER_clamp]
|Voltage   I(typ)   I(min)   I(max)
-1.5V     293.2mA    305.3mA    287.7mA
-1.228V   181.8mA    201.4mA    166.7mA
-1.073V   122mA      144.9mA    103.1mA
-980mV    90.12mA    113.2mA    73.54mA
-918mV    73.53mA    94.04mA    64.86mA
-887mV    67.91mA    85.47mA    63.12mA
-825mV    62.12mA    71.66mA    60.6mA
-732mV    58.2mA     61.46mA    57.08mA
43mV      30.98mA    31.08mA    30.46mA
694mV     2.693mA    838uA      3.668mA
787mV     0A         0A         0A
1.5V      0A         0A         0A
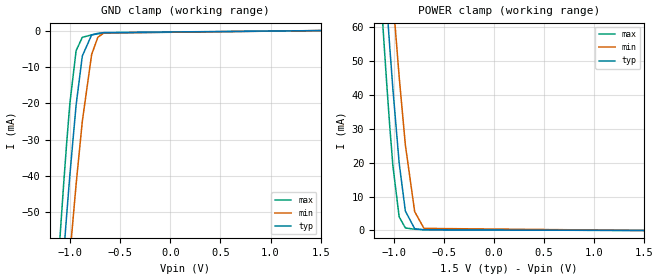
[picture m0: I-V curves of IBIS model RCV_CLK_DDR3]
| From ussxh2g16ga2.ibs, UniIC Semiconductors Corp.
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|   Model RCV_CLK_DDR3
[Model] RCV_CLK_DDR3
Model_type Input
Vinl =  0.615V
Vinh =  0.885V
C_comp   0.694pF   0.694pF   0.694pF
[Model Spec]
Vinh   0.885V   0.847V   0.922V
Vinl   0.615V   0.577V   0.652V
[Temperature Range]   25.000   0.105k   -40.000
[Voltage Range]   1.500V   1.425V   1.575V
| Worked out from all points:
|   GND clamp passes 1 mA (typ) near -0.77 V on its own axis
|   POWER clamp passes 1 mA (typ) near -0.82 V on its own axis
[GND_clamp]
|Voltage   I(typ)   I(min)   I(max)
-1.5V     -234.6mA   -239mA     -234.8mA
-1.128V   -84.6mA    -103.5mA   -67.29mA
-1.097V   -72.87mA   -92.79mA   -54.44mA
-1.066V   -61.4mA    -82.21mA   -42.08mA
-1.035V   -50.26mA   -71.82mA   -30.45mA
-1.004V   -39.59mA   -61.66mA   -19.95mA
-942mV    -20.46mA   -42.29mA   -5.525mA
-880mV    -6.991mA   -24.94mA   -1.848mA
-787mV    -1.189mA   -6.586mA   -1.176mA
-725mV    -751.2uA   -1.837mA   -911uA
-663mV    -545.9uA   -628.8uA   -670.4uA
1.5V      0A         0A         0A
[POWER_clamp]
|Voltage   I(typ)   I(min)   I(max)
-1.5V     266.1mA    279.5mA    256.6mA
-1.166V   107.8mA    132mA      86.28mA
-1.135V   93.86mA    118.9mA    71.47mA
-1.104V   80.17mA    105.9mA    57.08mA
-1.073V   66.81mA    93.18mA    43.3mA
-1.042V   53.89mA    80.68mA    30.42mA
-1.011V   41.58mA    68.49mA    18.97mA
-949mV    19.95mA    45.45mA    4.036mA
-887mV    5.734mA    25.27mA    743.9uA
-794mV    524.9uA    5.558mA    366.2uA
-701mV    192.7uA    614.3uA    227uA
1.5V      0A         0A         0A
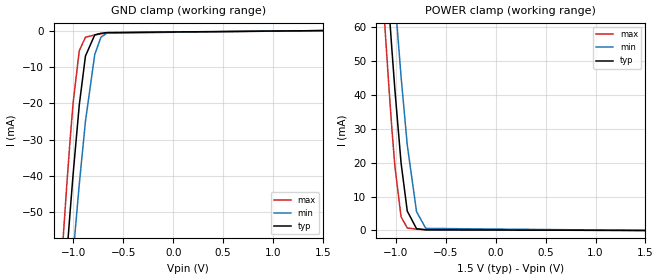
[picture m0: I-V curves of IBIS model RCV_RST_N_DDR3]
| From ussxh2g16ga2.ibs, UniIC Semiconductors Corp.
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|   Model RCV_RST_N_DDR3
[Model] RCV_RST_N_DDR3
Model_type Input
Vinl =  0.615V
Vinh =  0.885V
C_comp   0.725pF   0.725pF   0.725pF
[Model Spec]
Vinh   0.885V   0.847V   0.922V
Vinl   0.615V   0.577V   0.652V
[Temperature Range]   25.000   0.105k   -40.000
[Voltage Range]   1.500V   1.425V   1.575V
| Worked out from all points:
|   GND clamp passes 1 mA (typ) near -0.77 V on its own axis
|   POWER clamp passes 1 mA (typ) near -0.82 V on its own axis
[GND_clamp]
|Voltage   I(typ)   I(min)   I(max)
-1.5V     -234.6mA   -239mA     -234.8mA
-1.128V   -84.6mA    -103.5mA   -67.29mA
-1.097V   -72.88mA   -92.8mA    -54.45mA
-1.066V   -61.4mA    -82.21mA   -42.08mA
-1.035V   -50.27mA   -71.82mA   -30.45mA
-1.004V   -39.59mA   -61.66mA   -19.95mA
-942mV    -20.46mA   -42.29mA   -5.526mA
-880mV    -6.992mA   -24.95mA   -1.849mA
-787mV    -1.189mA   -6.586mA   -1.177mA
-725mV    -751.6uA   -1.837mA   -911.6uA
-663mV    -546.1uA   -628.9uA   -670.8uA
1.5V      0A         0A         0A
[POWER_clamp]
|Voltage   I(typ)   I(min)   I(max)
-1.5V     266.1mA    279.5mA    256.6mA
-1.166V   107.8mA    132mA      86.29mA
-1.135V   93.87mA    118.9mA    71.48mA
-1.104V   80.17mA    105.9mA    57.09mA
-1.073V   66.81mA    93.19mA    43.3mA
-1.042V   53.9mA     80.68mA    30.42mA
-1.011V   41.59mA    68.5mA     18.97mA
-949mV    19.96mA    45.45mA    4.037mA
-887mV    5.735mA    25.27mA    744.4uA
-794mV    525.1uA    5.558mA    366.5uA
-701mV    192.8uA    614.5uA    227.2uA
1.5V      0A         0A         0A
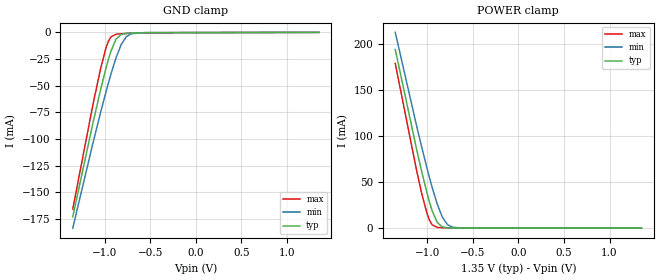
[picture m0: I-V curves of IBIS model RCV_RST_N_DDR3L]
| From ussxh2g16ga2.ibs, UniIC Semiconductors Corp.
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|   Model RCV_RST_N_DDR3L
[Model] RCV_RST_N_DDR3L
Model_type Input
Vinl =  0.540V
Vinh =  0.810V
C_comp   0.725pF   0.725pF   0.725pF
[Model Spec]
Vinh   0.810V   0.776V   0.860V
Vinl   0.540V   0.506V   0.590V
[Temperature Range]   25.000   0.105k   -40.000
[Voltage Range]   1.350V   1.283V   1.450V
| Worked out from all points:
|   GND clamp passes 1 mA (typ) near -0.77 V on its own axis
|   POWER clamp passes 1 mA (typ) near -0.82 V on its own axis
[GND_clamp]
|Voltage   I(typ)   I(min)   I(max)
-1.35V    -172.8mA   -183.4mA   -165.6mA
-1.126V   -83.84mA   -102.8mA   -66.45mA
-1.042V   -52.75mA   -74.15mA   -32.99mA
-986mV    -33.67mA   -55.88mA   -14.65mA
-958mV    -25.01mA   -47.14mA   -8.113mA
-930mV    -17.28mA   -38.74mA   -4.15mA
-874mV    -6.141mA   -23.43mA   -1.759mA
-818mV    -1.856mA   -11.28mA   -1.325mA
-762mV    -946uA     -3.998mA   -1.066mA
-706mV    -680.9uA   -1.262mA   -835.3uA
-566mV    -296.8uA   -244.1uA   -349.5uA
1.35V     0A         0A         0A
[POWER_clamp]
|Voltage   I(typ)   I(min)   I(max)
-1.35V    193.8mA    212.3mA    178.6mA
-1.114V   84.56mA    110.1mA    61.67mA
-1.058V   60.5mA     87.1mA     36.93mA
-1.002V   38.16mA    65.03mA    16.03mA
-974mV    28.06mA    54.49mA    8.423mA
-946mV    19.06mA    44.39mA    3.668mA
-890mV    6.184mA    26.15mA    784uA
-834mV    1.333mA    12mA       446.4uA
-778mV    401.9uA    3.891mA    340.1uA
-722mV    224.5uA    1.007mA    256.2uA
-610mV    98uA       118.3uA    117.2uA
1.35V     0A         0A         0A
